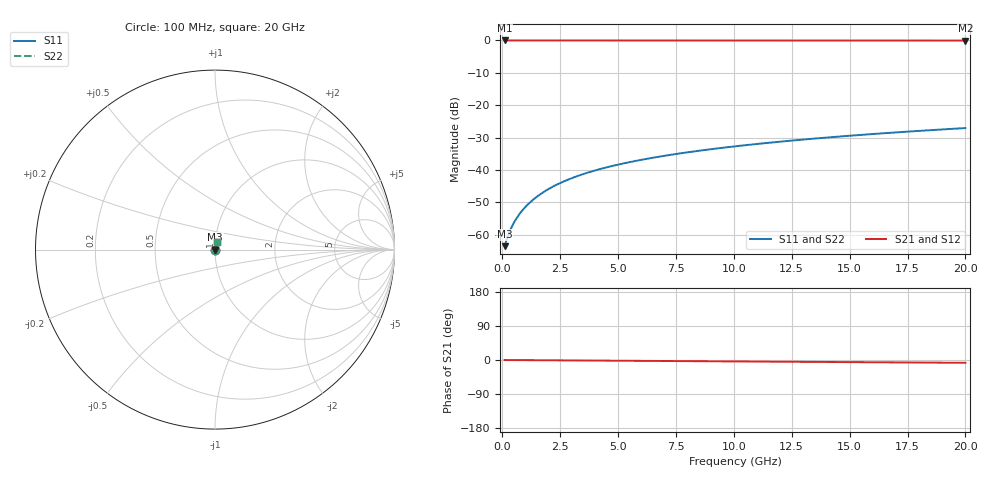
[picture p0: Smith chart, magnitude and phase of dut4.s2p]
! Touchstone file exported from HFSS 2026.1.0
!  File:  C:/ffzhzh/LocalFiles/Ansys_Project_Files/temp_test_BSMRDL_4_1782907238_46784.aedt
!  Generated:  08:01:51 PM Jul  1, 2026
!  Design:  BSMRDL
!  Project:  temp_test_BSMRDL_4_1782907238_46784
! Variables:
!  h_bsmrdl = 5.58um
!  h_ox = 20um
!  h_rdl = 5um
!  h_sub = 80um
!  h_tmrdl = 5um
!  h_tsv = 80um
!  h_via = 3um
!  l_bsmrdl = 111.44um
!  l_sub = 511.44um
!  l_tmrdl = 200um
!  m_sub = 200um
!  pitch = 25.56um
!  r_tsv = 6um
!  s_tmrdl = 10um
!  w_bsmrdl = 15.27um
!  w_sub = 500um
!  w_tmrdl = 12um
!  x_tsv_center1 = 206um
!  x_tsv_center2 = 332.71um
!  x_tsv_center3 = 544.71um
!  x_tsv_center4 = 671.42um
!  x_tsv_center5 = 883.42um
!  x_tsv_center6 = 1010.13um
# GHz S MA R 50.000000
! Terminal data exported
! Port[1] = BSM_RDL1_1_T1
! Port[2] = BSM_RDL1_1_T2
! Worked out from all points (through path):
!   200 points, 100 MHz to 20 GHz, reference 50 ohm
!   highest |S21| = -0.01 dB at 100 MHz (marker M1); lowest = 0.0 dB at 20 GHz (marker M2)
!   group delay of S21, straight-line fit = 1.02 ps
!   lowest |S11| = -63.6 dB at 100 MHz (marker M3), VSWR 1.00, Z = 50.1 + j0.0305 ohm
!   |S11| at or under -10 dB: start of sweep to end of sweep
!   |S22| runs from -63.6 to -27.1 dB; largest |S21 - S12| = 2.2e-15
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0.1  0.0006635 27.3  0.9994 -0.0  0.9994 -0.0  0.0006635 27.3
! Gamma 0 0 0 0
! Port Impedance 50 0 50 0
0.2  0.0008598 43.2  0.9994 -0.1  0.9994 -0.1  0.0008598 43.2
0.3  0.001081 51.9  0.9993 -0.1  0.9993 -0.1  0.001081 51.9
0.4  0.001305 57.5  0.9993 -0.2  0.9993 -0.2  0.001305 57.5
0.5  0.001529 61.5  0.9993 -0.2  0.9993 -0.2  0.001529 61.5
0.6  0.001754 64.7  0.9993 -0.2  0.9993 -0.2  0.001754 64.7
0.8  0.002213 69.2  0.9992 -0.3  0.9992 -0.3  0.002213 69.2
1  0.002681 72.2  0.9992 -0.4  0.9992 -0.4  0.002681 72.2
1.2  0.003155 74.3  0.9992 -0.5  0.9992 -0.5  0.003155 74.3
1.4  0.003632 75.9  0.9991 -0.5  0.9991 -0.5  0.003632 75.9
1.7  0.004352 77.5  0.9991 -0.7  0.9991 -0.7  0.004352 77.5
2.2  0.005552 79.0  0.999 -0.8  0.999 -0.8  0.005552 79.0
2.8  0.006983 80.0  0.9989 -1.1  0.9989 -1.1  0.006983 80.0
3.5  0.008629 80.5  0.9987 -1.3  0.9987 -1.3  0.008629 80.5
4.2  0.01025 80.8  0.9986 -1.6  0.9986 -1.6  0.01025 80.8
5  0.01207 80.8  0.9984 -1.9  0.9984 -1.9  0.01207 80.8
6.8  0.01607 80.8  0.998 -2.6  0.998 -2.6  0.01607 80.8
8.3  0.01935 80.7  0.9977 -3.1  0.9977 -3.1  0.01935 80.7
10.1  0.02324 80.5  0.9974 -3.8  0.9974 -3.8  0.02324 80.5
13.4  0.03031 79.9  0.9968 -5.0  0.9968 -5.0  0.03031 79.9
16.7  0.03733 79.1  0.9963 -6.2  0.9963 -6.2  0.03733 79.1
20  0.04429 78.3  0.9957 -7.4  0.9957 -7.4  0.04429 78.3
